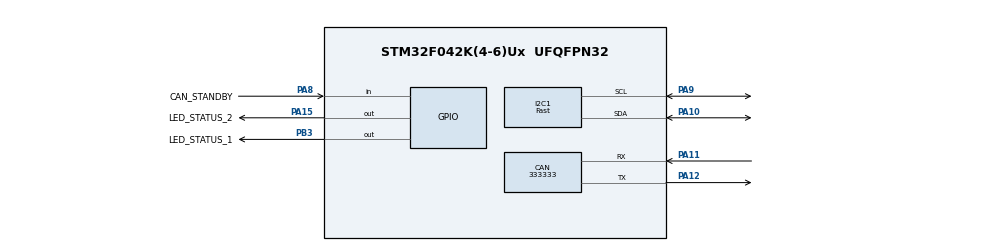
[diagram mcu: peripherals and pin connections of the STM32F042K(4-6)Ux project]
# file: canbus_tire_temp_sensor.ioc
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CAN.CalculateBaudRate=333333
CAN.CalculateTimeBit=3000
CAN.CalculateTimeQuantum=1000.0
I2C1.I2C_Speed_Mode=I2C_Fast
I2C1.Timing=0x00300617
Mcu.Family=STM32F0
Mcu.Name=STM32F042K(4-6)Ux
Mcu.Package=UFQFPN32
PA10.Mode=I2C
PA10.Signal=I2C1_SDA
PA11.Mode=CAN_Activate
PA11.Signal=CAN_RX
PA12.Mode=CAN_Activate
PA12.Signal=CAN_TX
PA13.Mode=Serial_Wire
PA13.Signal=SYS_SWDIO
PA14.Mode=Serial_Wire
PA14.Signal=SYS_SWCLK
PA15.GPIO_Label=LED_STATUS_2
PA15.Signal=GPIO_Output
PA8.GPIO_Label=CAN_STANDBY
PA8.Signal=GPIO_Input
PA9.Mode=I2C
PA9.Signal=I2C1_SCL
PB3.GPIO_Label=LED_STATUS_1
PB3.Signal=GPIO_Output
PF0-OSC_IN.Mode=HSE-External-Oscillator
PF0-OSC_IN.Signal=RCC_OSC_IN
PF1-OSC_OUT.Mode=HSE-External-Oscillator
PF1-OSC_OUT.Signal=RCC_OSC_OUT
ProjectManager.HeapSize=0x200
ProjectManager.StackSize=0x400
ProjectManager.TargetToolchain=STM32CubeIDE
RCC.AHBFreq_Value=16000000
RCC.APB1Freq_Value=16000000
RCC.APB1TimFreq_Value=16000000
RCC.HCLKFreq_Value=16000000
RCC.HSE_VALUE=16000000
RCC.I2c1ClockSelection=RCC_I2C1CLKSOURCE_SYSCLK
RCC.PLLSourceVirtual=RCC_PLLSOURCE_HSE
RCC.SYSCLKFreq_VALUE=16000000
RCC.SYSCLKSource=RCC_SYSCLKSOURCE_HSE
board=custom

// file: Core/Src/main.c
/* USER CODE BEGIN Header */
/**
  ******************************************************************************
  * @file           : main.c
  * @brief          : Main program body
  ******************************************************************************
  * @attention
  *
  * Copyright (c) 2025 STMicroelectronics.
  * All rights reserved.
  *
  * This software is licensed under terms that can be found in the LICENSE file
  * in the root directory of this software component.
  * If no LICENSE file comes with this software, it is provided AS-IS.
  *
  ******************************************************************************
  */
/* USER CODE END Header */
#include "main.h"

/* USER CODE BEGIN Includes */

#include "can.h"
/* USER CODE END Includes */

CAN_HandleTypeDef hcan;

I2C_HandleTypeDef hi2c1;

void SystemClock_Config(void);
static void MX_GPIO_Init(void);
static void MX_CAN_Init(void);
static void MX_I2C1_Init(void);

int main(void)
{

  /* MCU Configuration--------------------------------------------------------*/

  /* Reset of all peripherals, Initializes the Flash interface and the Systick. */
  HAL_Init();

  /* Configure the system clock */
  SystemClock_Config();

  /* Initialize all configured peripherals */
  MX_GPIO_Init();
  MX_CAN_Init();
  MX_I2C1_Init();
  /* USER CODE BEGIN 2 */

  /* Initialize CAN application module */
  if (CANAPP_Init(CAN_DEFAULT_BASE_ID, 1000000) != HAL_OK)
  {
    Error_Handler();
  }

  /* USER CODE END 2 */
  while (1)
  {

    /* USER CODE BEGIN 3 */
    static uint32_t lastTx = 0;
    uint8_t data[8] = {0};

    if (HAL_GetTick() - lastTx >= 100)
    {
      uint32_t base = CANAPP_GetBaseID();
      CANAPP_Send(base + 1, data, 8);
      CANAPP_Send(base + 2, data, 8);
      CANAPP_Send(base + 3, data, 8);
      CANAPP_Send(base + 4, data, 8);
      lastTx = HAL_GetTick();
    }

    CAN_RxHeaderTypeDef rxHeader;
    uint8_t rxData[8];
    if (CANAPP_Receive(&rxHeader, rxData) == HAL_OK)
    {
      if (rxHeader.StdId == CAN_CONFIG_MSG_ID && rxHeader.DLC >= 6)
      {
        uint32_t newBase = (rxData[0] << 8) | rxData[1];
        uint32_t newBaud = (rxData[2] << 24) | (rxData[3] << 16) |
                            (rxData[4] << 8) | rxData[5];
        CANAPP_UpdateConfig(newBase, newBaud);
      }
    }
  }
  /* USER CODE END 3 */
}

void SystemClock_Config(void)
{
  RCC_OscInitTypeDef RCC_OscInitStruct = {0};
  RCC_ClkInitTypeDef RCC_ClkInitStruct = {0};
  RCC_PeriphCLKInitTypeDef PeriphClkInit = {0};

  /** Initializes the RCC Oscillators according to the specified parameters
  * in the RCC_OscInitTypeDef structure.
  */
  RCC_OscInitStruct.OscillatorType = RCC_OSCILLATORTYPE_HSI;
  RCC_OscInitStruct.HSIState = RCC_HSI_ON;
  RCC_OscInitStruct.HSICalibrationValue = RCC_HSICALIBRATION_DEFAULT;
  RCC_OscInitStruct.PLL.PLLState = RCC_PLL_NONE;
  if (HAL_RCC_OscConfig(&RCC_OscInitStruct) != HAL_OK)
  {
    Error_Handler();
  }

  /** Initializes the CPU, AHB and APB buses clocks
  */
  RCC_ClkInitStruct.ClockType = RCC_CLOCKTYPE_HCLK|RCC_CLOCKTYPE_SYSCLK
                              |RCC_CLOCKTYPE_PCLK1;
  RCC_ClkInitStruct.SYSCLKSource = RCC_SYSCLKSOURCE_HSI;
  RCC_ClkInitStruct.AHBCLKDivider = RCC_SYSCLK_DIV1;
  RCC_ClkInitStruct.APB1CLKDivider = RCC_HCLK_DIV1;

  if (HAL_RCC_ClockConfig(&RCC_ClkInitStruct, FLASH_LATENCY_0) != HAL_OK)
  {
    Error_Handler();
  }
  PeriphClkInit.PeriphClockSelection = RCC_PERIPHCLK_I2C1;
  PeriphClkInit.I2c1ClockSelection = RCC_I2C1CLKSOURCE_HSI;
  if (HAL_RCCEx_PeriphCLKConfig(&PeriphClkInit) != HAL_OK)
  {
    Error_Handler();
  }
}

static void MX_CAN_Init(void)
{

  hcan.Instance = CAN;
  hcan.Init.Prescaler = 16;
  hcan.Init.Mode = CAN_MODE_NORMAL;
  hcan.Init.SyncJumpWidth = CAN_SJW_1TQ;
  hcan.Init.TimeSeg1 = CAN_BS1_1TQ;
  hcan.Init.TimeSeg2 = CAN_BS2_1TQ;
  hcan.Init.TimeTriggeredMode = DISABLE;
  hcan.Init.AutoBusOff = DISABLE;
  hcan.Init.AutoWakeUp = DISABLE;
  hcan.Init.AutoRetransmission = DISABLE;
  hcan.Init.ReceiveFifoLocked = DISABLE;
  hcan.Init.TransmitFifoPriority = DISABLE;
  if (HAL_CAN_Init(&hcan) != HAL_OK)
  {
    Error_Handler();
  }

}

static void MX_I2C1_Init(void)
{

  hi2c1.Instance = I2C1;
  hi2c1.Init.Timing = 0x00201D2B;
  hi2c1.Init.OwnAddress1 = 0;
  hi2c1.Init.AddressingMode = I2C_ADDRESSINGMODE_7BIT;
  hi2c1.Init.DualAddressMode = I2C_DUALADDRESS_DISABLE;
  hi2c1.Init.OwnAddress2 = 0;
  hi2c1.Init.OwnAddress2Masks = I2C_OA2_NOMASK;
  hi2c1.Init.GeneralCallMode = I2C_GENERALCALL_DISABLE;
  hi2c1.Init.NoStretchMode = I2C_NOSTRETCH_DISABLE;
  if (HAL_I2C_Init(&hi2c1) != HAL_OK)
  {
    Error_Handler();
  }

  /** Configure Analogue filter
  */
  if (HAL_I2CEx_ConfigAnalogFilter(&hi2c1, I2C_ANALOGFILTER_ENABLE) != HAL_OK)
  {
    Error_Handler();
  }

  /** Configure Digital filter
  */
  if (HAL_I2CEx_ConfigDigitalFilter(&hi2c1, 0) != HAL_OK)
  {
    Error_Handler();
  }

}

static void MX_GPIO_Init(void)
{
  GPIO_InitTypeDef GPIO_InitStruct = {0};

  /* GPIO Ports Clock Enable */
  __HAL_RCC_GPIOF_CLK_ENABLE();
  __HAL_RCC_GPIOA_CLK_ENABLE();
  __HAL_RCC_GPIOB_CLK_ENABLE();

  /*Configure GPIO pin Output Level */
  HAL_GPIO_WritePin(GPIOA, CAN_STANDBY_Pin|LED_STATUS_2_Pin, GPIO_PIN_RESET);

  /*Configure GPIO pin Output Level */
  HAL_GPIO_WritePin(LED_STATUS_1_GPIO_Port, LED_STATUS_1_Pin, GPIO_PIN_RESET);

  /*Configure GPIO pins : CAN_STANDBY_Pin LED_STATUS_2_Pin */
  GPIO_InitStruct.Pin = CAN_STANDBY_Pin|LED_STATUS_2_Pin;
  GPIO_InitStruct.Mode = GPIO_MODE_OUTPUT_PP;
  GPIO_InitStruct.Pull = GPIO_NOPULL;
  GPIO_InitStruct.Speed = GPIO_SPEED_FREQ_LOW;
  HAL_GPIO_Init(GPIOA, &GPIO_InitStruct);

  /*Configure GPIO pin : LED_STATUS_1_Pin */
  GPIO_InitStruct.Pin = LED_STATUS_1_Pin;
  GPIO_InitStruct.Mode = GPIO_MODE_OUTPUT_PP;
  GPIO_InitStruct.Pull = GPIO_NOPULL;
  GPIO_InitStruct.Speed = GPIO_SPEED_FREQ_LOW;
  HAL_GPIO_Init(LED_STATUS_1_GPIO_Port, &GPIO_InitStruct);

}

void Error_Handler(void)
{
  __disable_irq();
  while (1)
  {
  }
}
